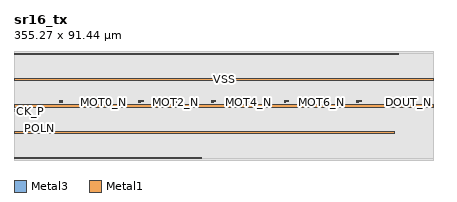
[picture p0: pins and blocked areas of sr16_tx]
MACRO sr16_tx
  CLASS BLOCK ;
  FOREIGN sr16_tx ;
  ORIGIN 0.150 1.000 ;
  SIZE 355.270 BY 91.440 ;
  PIN CK_N
    DIRECTION INPUT ;
    USE SIGNAL ;
    PORT
      LAYER Metal3 ;
        RECT 0.000 41.120 0.150 41.720 ;
    END
  END CK_N
  PIN CK_P
    DIRECTION INPUT ;
    USE SIGNAL ;
    PORT
      LAYER Metal3 ;
        RECT 0.000 40.020 0.150 40.620 ;
    END
  END CK_P
  PIN CLK_W_N
    DIRECTION INPUT ;
    USE SIGNAL ;
    PORT
      LAYER Metal3 ;
        RECT 38.250 47.880 40.470 48.180 ;
    END
  END CLK_W_N
  PIN CLK_W_P
    DIRECTION INPUT ;
    USE SIGNAL ;
    PORT
      LAYER Metal3 ;
        RECT 38.250 48.930 40.470 49.230 ;
    END
  END CLK_W_P
  PIN MOT0_N
    DIRECTION INPUT ;
    USE SIGNAL ;
    PORT
      LAYER Metal3 ;
        RECT 74.650 47.770 76.215 48.070 ;
    END
  END MOT0_N
  PIN MOT0_P
    DIRECTION INPUT ;
    USE SIGNAL ;
    PORT
      LAYER Metal3 ;
        RECT 74.650 48.870 78.460 49.170 ;
    END
  END MOT0_P
  PIN MOT1_N
    DIRECTION INPUT ;
    USE SIGNAL ;
    PORT
      LAYER Metal3 ;
        RECT 105.370 47.770 106.935 48.070 ;
    END
  END MOT1_N
  PIN MOT1_P
    DIRECTION INPUT ;
    USE SIGNAL ;
    PORT
      LAYER Metal3 ;
        RECT 105.370 48.870 109.180 49.170 ;
    END
  END MOT1_P
  PIN MOT2_N
    DIRECTION INPUT ;
    USE SIGNAL ;
    PORT
      LAYER Metal3 ;
        RECT 136.090 47.770 137.655 48.070 ;
    END
  END MOT2_N
  PIN MOT2_P
    DIRECTION INPUT ;
    USE SIGNAL ;
    PORT
      LAYER Metal3 ;
        RECT 136.090 48.870 139.900 49.170 ;
    END
  END MOT2_P
  PIN MOT3_N
    DIRECTION INPUT ;
    USE SIGNAL ;
    PORT
      LAYER Metal3 ;
        RECT 166.810 47.770 168.375 48.070 ;
    END
  END MOT3_N
  PIN MOT3_P
    DIRECTION INPUT ;
    USE SIGNAL ;
    PORT
      LAYER Metal3 ;
        RECT 166.810 48.870 170.620 49.170 ;
    END
  END MOT3_P
  PIN MOT4_N
    DIRECTION INPUT ;
    USE SIGNAL ;
    PORT
      LAYER Metal3 ;
        RECT 197.530 47.770 199.095 48.070 ;
    END
  END MOT4_N
  PIN MOT4_P
    DIRECTION INPUT ;
    USE SIGNAL ;
    PORT
      LAYER Metal3 ;
        RECT 197.530 48.870 201.340 49.170 ;
    END
  END MOT4_P
  PIN MOT5_N
    DIRECTION INPUT ;
    USE SIGNAL ;
    PORT
      LAYER Metal3 ;
        RECT 228.250 47.770 229.815 48.070 ;
    END
  END MOT5_N
  PIN MOT5_P
    DIRECTION INPUT ;
    USE SIGNAL ;
    PORT
      LAYER Metal3 ;
        RECT 228.250 48.870 232.060 49.170 ;
    END
  END MOT5_P
  PIN MOT6_N
    DIRECTION INPUT ;
    USE SIGNAL ;
    PORT
      LAYER Metal3 ;
        RECT 258.970 47.770 260.535 48.070 ;
    END
  END MOT6_N
  PIN MOT6_P
    DIRECTION INPUT ;
    USE SIGNAL ;
    PORT
      LAYER Metal3 ;
        RECT 258.970 48.870 262.780 49.170 ;
    END
  END MOT6_P
  PIN MOT7_N
    DIRECTION INPUT ;
    USE SIGNAL ;
    PORT
      LAYER Metal3 ;
        RECT 289.690 47.770 291.255 48.070 ;
    END
  END MOT7_N
  PIN MOT7_P
    DIRECTION INPUT ;
    USE SIGNAL ;
    PORT
      LAYER Metal3 ;
        RECT 289.690 48.870 293.500 49.170 ;
    END
  END MOT7_P
  PIN DOUT_N
    DIRECTION OUTPUT ;
    USE SIGNAL ;
    PORT
      LAYER Metal3 ;
        RECT 352.900 47.720 353.350 48.320 ;
    END
  END DOUT_N
  PIN DOUT_P
    DIRECTION OUTPUT ;
    USE SIGNAL ;
    PORT
      LAYER Metal3 ;
        RECT 352.390 48.970 353.350 49.270 ;
    END
  END DOUT_P
  PIN POLN
    DIRECTION INPUT ;
    USE SIGNAL ;
    PORT
      LAYER Metal3 ;
        RECT 21.450 25.370 22.120 26.390 ;
    END
  END POLN
  PIN VDD
    DIRECTION INOUT ;
    USE POWER ;
    PORT
      LAYER Metal1 ;
        RECT 0.000 0.000 158.320 1.000 ;
        RECT 0.000 43.720 355.120 45.720 ;
        RECT 0.000 88.440 325.360 89.440 ;
    END
  END VDD
  PIN VSS
    DIRECTION INOUT ;
    USE GROUND ;
    PORT
      LAYER Metal1 ;
        RECT 0.000 21.360 321.520 23.360 ;
        RECT 0.000 66.080 355.120 68.080 ;
    END
  END VSS
  OBS
    LAYER Metal1 ;
      RECT -0.150 -1.000 355.120 0.000 ;
      RECT -0.150 0.000 0.000 1.000 ;
      RECT 158.320 0.000 355.120 1.000 ;
      RECT -0.150 1.000 355.120 21.360 ;
      RECT -0.150 21.360 0.000 23.360 ;
      RECT 321.520 21.360 355.120 23.360 ;
      RECT -0.150 23.360 355.120 43.720 ;
      RECT -0.150 43.720 0.000 45.720 ;
      RECT -0.150 45.720 355.120 66.080 ;
      RECT -0.150 66.080 0.000 68.080 ;
      RECT -0.150 68.080 355.120 88.440 ;
      RECT -0.150 88.440 0.000 89.440 ;
      RECT 325.360 88.440 355.120 89.440 ;
      RECT -0.150 89.440 355.120 90.440 ;
    LAYER Metal2 ;
      RECT -0.150 -1.000 355.120 0.000 ;
      RECT -0.150 0.000 0.000 1.000 ;
      RECT 158.320 0.000 355.120 1.000 ;
      RECT -0.150 1.000 355.120 21.360 ;
      RECT -0.150 21.360 0.000 23.360 ;
      RECT 321.520 21.360 355.120 23.360 ;
      RECT -0.150 23.360 355.120 43.720 ;
      RECT -0.150 43.720 0.000 45.720 ;
      RECT -0.150 45.720 355.120 66.080 ;
      RECT -0.150 66.080 0.000 68.080 ;
      RECT -0.150 68.080 355.120 88.440 ;
      RECT -0.150 88.440 0.000 89.440 ;
      RECT 325.360 88.440 355.120 89.440 ;
      RECT -0.150 89.440 355.120 90.440 ;
    LAYER Metal3 ;
      RECT -0.150 -1.000 355.120 0.000 ;
      RECT -0.150 0.000 0.000 1.000 ;
      RECT 158.320 0.000 355.120 1.000 ;
      RECT -0.150 1.000 355.120 21.360 ;
      RECT -0.150 21.360 0.000 23.360 ;
      RECT 321.520 21.360 355.120 23.360 ;
      RECT -0.150 23.360 355.120 24.890 ;
      RECT -0.150 24.890 20.970 26.870 ;
      RECT 22.600 24.890 355.120 26.870 ;
      RECT -0.150 26.870 355.120 39.540 ;
      RECT 0.630 39.540 355.120 40.640 ;
      RECT 0.630 40.640 355.120 41.100 ;
      RECT 0.630 41.100 355.120 42.200 ;
      RECT -0.150 42.200 355.120 43.720 ;
      RECT -0.150 43.720 0.000 45.720 ;
      RECT -0.150 45.720 355.120 47.240 ;
      RECT -0.150 47.240 352.420 47.290 ;
      RECT 353.830 47.240 355.120 47.290 ;
      RECT -0.150 47.290 74.170 47.400 ;
      RECT 76.695 47.290 104.890 47.400 ;
      RECT 107.415 47.290 135.610 47.400 ;
      RECT 138.135 47.290 166.330 47.400 ;
      RECT 168.855 47.290 197.050 47.400 ;
      RECT 199.575 47.290 227.770 47.400 ;
      RECT 230.295 47.290 258.490 47.400 ;
      RECT 261.015 47.290 289.210 47.400 ;
      RECT 291.735 47.290 352.420 47.400 ;
      RECT 353.830 47.290 355.120 47.400 ;
      RECT -0.150 47.400 37.770 48.390 ;
      RECT 40.950 47.400 74.170 48.390 ;
      RECT 76.695 47.400 104.890 48.390 ;
      RECT 107.415 47.400 135.610 48.390 ;
      RECT 138.135 47.400 166.330 48.390 ;
      RECT 168.855 47.400 197.050 48.390 ;
      RECT 199.575 47.400 227.770 48.390 ;
      RECT 230.295 47.400 258.490 48.390 ;
      RECT 261.015 47.400 289.210 48.390 ;
      RECT 291.735 47.400 352.420 48.390 ;
      RECT 353.830 47.400 355.120 48.390 ;
      RECT -0.150 48.390 37.770 48.450 ;
      RECT 40.950 48.390 74.170 48.450 ;
      RECT 78.940 48.390 104.890 48.450 ;
      RECT 109.660 48.390 135.610 48.450 ;
      RECT 140.380 48.390 166.330 48.450 ;
      RECT 171.100 48.390 197.050 48.450 ;
      RECT 201.820 48.390 227.770 48.450 ;
      RECT 232.540 48.390 258.490 48.450 ;
      RECT 263.260 48.390 289.210 48.450 ;
      RECT 293.980 48.390 352.420 48.450 ;
      RECT 353.830 48.390 355.120 48.450 ;
      RECT -0.150 48.450 37.770 48.490 ;
      RECT 40.950 48.450 74.170 48.490 ;
      RECT 78.940 48.450 104.890 48.490 ;
      RECT 109.660 48.450 135.610 48.490 ;
      RECT 140.380 48.450 166.330 48.490 ;
      RECT 171.100 48.450 197.050 48.490 ;
      RECT 201.820 48.450 227.770 48.490 ;
      RECT 232.540 48.450 258.490 48.490 ;
      RECT 263.260 48.450 289.210 48.490 ;
      RECT 293.980 48.450 352.420 48.490 ;
      RECT 353.830 48.450 355.120 48.490 ;
      RECT -0.150 48.490 37.770 48.550 ;
      RECT 40.950 48.490 74.170 48.550 ;
      RECT 78.940 48.490 104.890 48.550 ;
      RECT 109.660 48.490 135.610 48.550 ;
      RECT 140.380 48.490 166.330 48.550 ;
      RECT 171.100 48.490 197.050 48.550 ;
      RECT 201.820 48.490 227.770 48.550 ;
      RECT 232.540 48.490 258.490 48.550 ;
      RECT 263.260 48.490 289.210 48.550 ;
      RECT 293.980 48.490 351.910 48.550 ;
      RECT 353.830 48.490 355.120 48.550 ;
      RECT -0.150 48.550 37.770 48.660 ;
      RECT 40.950 48.550 74.170 48.660 ;
      RECT 78.940 48.550 104.890 48.660 ;
      RECT 109.660 48.550 135.610 48.660 ;
      RECT 140.380 48.550 166.330 48.660 ;
      RECT 171.100 48.550 197.050 48.660 ;
      RECT 201.820 48.550 227.770 48.660 ;
      RECT 232.540 48.550 258.490 48.660 ;
      RECT 263.260 48.550 289.210 48.660 ;
      RECT 293.980 48.550 351.910 48.660 ;
      RECT 353.830 48.550 355.120 48.660 ;
      RECT -0.150 48.660 37.770 48.800 ;
      RECT 40.950 48.660 74.170 48.800 ;
      RECT 78.940 48.660 104.890 48.800 ;
      RECT 109.660 48.660 135.610 48.800 ;
      RECT 140.380 48.660 166.330 48.800 ;
      RECT 171.100 48.660 197.050 48.800 ;
      RECT 201.820 48.660 227.770 48.800 ;
      RECT 232.540 48.660 258.490 48.800 ;
      RECT 263.260 48.660 289.210 48.800 ;
      RECT 293.980 48.660 351.910 48.800 ;
      RECT 353.830 48.660 355.120 48.800 ;
      RECT -0.150 48.800 37.770 49.650 ;
      RECT 40.950 48.800 74.170 49.650 ;
      RECT 78.940 48.800 104.890 49.650 ;
      RECT 109.660 48.800 135.610 49.650 ;
      RECT 140.380 48.800 166.330 49.650 ;
      RECT 171.100 48.800 197.050 49.650 ;
      RECT 201.820 48.800 227.770 49.650 ;
      RECT 232.540 48.800 258.490 49.650 ;
      RECT 263.260 48.800 289.210 49.650 ;
      RECT 293.980 48.800 351.910 49.650 ;
      RECT 353.830 48.800 355.120 49.650 ;
      RECT -0.150 49.650 37.770 49.710 ;
      RECT 40.950 49.650 351.910 49.710 ;
      RECT 353.830 49.650 355.120 49.710 ;
      RECT -0.150 49.710 351.910 49.750 ;
      RECT 353.830 49.710 355.120 49.750 ;
      RECT -0.150 49.750 355.120 66.080 ;
      RECT -0.150 66.080 0.000 68.080 ;
      RECT -0.150 68.080 355.120 88.440 ;
      RECT -0.150 88.440 0.000 89.440 ;
      RECT 325.360 88.440 355.120 89.440 ;
      RECT -0.150 89.440 355.120 90.440 ;
    LAYER Metal4 ;
      RECT -0.150 -1.000 355.120 0.000 ;
      RECT -0.150 0.000 0.000 1.000 ;
      RECT 158.320 0.000 355.120 1.000 ;
      RECT -0.150 1.000 355.120 21.360 ;
      RECT -0.150 21.360 0.000 23.360 ;
      RECT 321.520 21.360 355.120 23.360 ;
      RECT -0.150 23.360 355.120 24.890 ;
      RECT -0.150 24.890 20.970 26.870 ;
      RECT 22.600 24.890 355.120 26.870 ;
      RECT -0.150 26.870 355.120 39.540 ;
      RECT 0.630 39.540 355.120 40.640 ;
      RECT 0.630 40.640 355.120 41.100 ;
      RECT 0.630 41.100 355.120 42.200 ;
      RECT -0.150 42.200 355.120 43.720 ;
      RECT -0.150 43.720 0.000 45.720 ;
      RECT -0.150 45.720 355.120 47.240 ;
      RECT -0.150 47.240 352.420 47.290 ;
      RECT 353.830 47.240 355.120 47.290 ;
      RECT -0.150 47.290 74.170 47.400 ;
      RECT 76.695 47.290 104.890 47.400 ;
      RECT 107.415 47.290 135.610 47.400 ;
      RECT 138.135 47.290 166.330 47.400 ;
      RECT 168.855 47.290 197.050 47.400 ;
      RECT 199.575 47.290 227.770 47.400 ;
      RECT 230.295 47.290 258.490 47.400 ;
      RECT 261.015 47.290 289.210 47.400 ;
      RECT 291.735 47.290 352.420 47.400 ;
      RECT 353.830 47.290 355.120 47.400 ;
      RECT -0.150 47.400 37.770 48.390 ;
      RECT 40.950 47.400 74.170 48.390 ;
      RECT 76.695 47.400 104.890 48.390 ;
      RECT 107.415 47.400 135.610 48.390 ;
      RECT 138.135 47.400 166.330 48.390 ;
      RECT 168.855 47.400 197.050 48.390 ;
      RECT 199.575 47.400 227.770 48.390 ;
      RECT 230.295 47.400 258.490 48.390 ;
      RECT 261.015 47.400 289.210 48.390 ;
      RECT 291.735 47.400 352.420 48.390 ;
      RECT 353.830 47.400 355.120 48.390 ;
      RECT -0.150 48.390 37.770 48.450 ;
      RECT 40.950 48.390 74.170 48.450 ;
      RECT 78.940 48.390 104.890 48.450 ;
      RECT 109.660 48.390 135.610 48.450 ;
      RECT 140.380 48.390 166.330 48.450 ;
      RECT 171.100 48.390 197.050 48.450 ;
      RECT 201.820 48.390 227.770 48.450 ;
      RECT 232.540 48.390 258.490 48.450 ;
      RECT 263.260 48.390 289.210 48.450 ;
      RECT 293.980 48.390 352.420 48.450 ;
      RECT 353.830 48.390 355.120 48.450 ;
      RECT -0.150 48.450 37.770 48.490 ;
      RECT 40.950 48.450 74.170 48.490 ;
      RECT 78.940 48.450 104.890 48.490 ;
      RECT 109.660 48.450 135.610 48.490 ;
      RECT 140.380 48.450 166.330 48.490 ;
      RECT 171.100 48.450 197.050 48.490 ;
      RECT 201.820 48.450 227.770 48.490 ;
      RECT 232.540 48.450 258.490 48.490 ;
      RECT 263.260 48.450 289.210 48.490 ;
      RECT 293.980 48.450 352.420 48.490 ;
      RECT 353.830 48.450 355.120 48.490 ;
      RECT -0.150 48.490 37.770 48.550 ;
      RECT 40.950 48.490 74.170 48.550 ;
      RECT 78.940 48.490 104.890 48.550 ;
      RECT 109.660 48.490 135.610 48.550 ;
      RECT 140.380 48.490 166.330 48.550 ;
      RECT 171.100 48.490 197.050 48.550 ;
      RECT 201.820 48.490 227.770 48.550 ;
      RECT 232.540 48.490 258.490 48.550 ;
      RECT 263.260 48.490 289.210 48.550 ;
      RECT 293.980 48.490 351.910 48.550 ;
      RECT 353.830 48.490 355.120 48.550 ;
      RECT -0.150 48.550 37.770 48.660 ;
      RECT 40.950 48.550 74.170 48.660 ;
      RECT 78.940 48.550 104.890 48.660 ;
      RECT 109.660 48.550 135.610 48.660 ;
      RECT 140.380 48.550 166.330 48.660 ;
      RECT 171.100 48.550 197.050 48.660 ;
      RECT 201.820 48.550 227.770 48.660 ;
      RECT 232.540 48.550 258.490 48.660 ;
      RECT 263.260 48.550 289.210 48.660 ;
      RECT 293.980 48.550 351.910 48.660 ;
      RECT 353.830 48.550 355.120 48.660 ;
      RECT -0.150 48.660 37.770 48.800 ;
      RECT 40.950 48.660 74.170 48.800 ;
      RECT 78.940 48.660 104.890 48.800 ;
      RECT 109.660 48.660 135.610 48.800 ;
      RECT 140.380 48.660 166.330 48.800 ;
      RECT 171.100 48.660 197.050 48.800 ;
      RECT 201.820 48.660 227.770 48.800 ;
      RECT 232.540 48.660 258.490 48.800 ;
      RECT 263.260 48.660 289.210 48.800 ;
      RECT 293.980 48.660 351.910 48.800 ;
      RECT 353.830 48.660 355.120 48.800 ;
      RECT -0.150 48.800 37.770 49.650 ;
      RECT 40.950 48.800 74.170 49.650 ;
      RECT 78.940 48.800 104.890 49.650 ;
      RECT 109.660 48.800 135.610 49.650 ;
      RECT 140.380 48.800 166.330 49.650 ;
      RECT 171.100 48.800 197.050 49.650 ;
      RECT 201.820 48.800 227.770 49.650 ;
      RECT 232.540 48.800 258.490 49.650 ;
      RECT 263.260 48.800 289.210 49.650 ;
      RECT 293.980 48.800 351.910 49.650 ;
      RECT 353.830 48.800 355.120 49.650 ;
      RECT -0.150 49.650 37.770 49.710 ;
      RECT 40.950 49.650 351.910 49.710 ;
      RECT 353.830 49.650 355.120 49.710 ;
      RECT -0.150 49.710 351.910 49.750 ;
      RECT 353.830 49.710 355.120 49.750 ;
      RECT -0.150 49.750 355.120 66.080 ;
      RECT -0.150 66.080 0.000 68.080 ;
      RECT -0.150 68.080 355.120 88.440 ;
      RECT -0.150 88.440 0.000 89.440 ;
      RECT 325.360 88.440 355.120 89.440 ;
      RECT -0.150 89.440 355.120 90.440 ;
    LAYER Metal4 ;
      RECT 265.235 26.175 265.525 26.465 ;
      RECT 265.280 26.465 265.480 32.355 ;
      RECT 265.235 32.355 265.525 32.645 ;
      RECT 192.275 40.175 192.565 40.465 ;
      RECT 192.320 40.465 192.520 46.395 ;
      RECT 192.275 46.395 192.565 46.685 ;
      RECT 227.755 41.275 228.045 41.565 ;
      RECT 227.800 41.565 228.000 46.915 ;
      RECT 227.755 46.915 228.045 47.205 ;
      RECT 223.915 42.755 224.205 43.045 ;
      RECT 223.960 43.045 224.160 47.875 ;
      RECT 223.915 47.875 224.205 48.165 ;
      RECT 285.355 43.275 285.645 43.565 ;
      RECT 285.400 43.565 285.600 47.875 ;
      RECT 285.355 47.875 285.645 48.165 ;
      RECT 228.755 40.175 229.045 40.465 ;
      RECT 228.800 40.465 229.000 50.035 ;
      RECT 228.755 50.035 229.045 50.325 ;
      RECT 264.235 41.275 264.525 41.565 ;
      RECT 264.280 41.565 264.480 50.555 ;
      RECT 264.235 50.555 264.525 50.845 ;
      RECT 265.235 40.175 265.525 40.465 ;
      RECT 265.280 40.465 265.480 51.075 ;
      RECT 265.235 51.075 265.525 51.365 ;
      RECT 189.355 41.275 189.645 41.565 ;
      RECT 189.400 41.565 189.600 51.595 ;
      RECT 189.355 51.595 189.645 51.885 ;
      RECT 190.355 40.175 190.645 40.465 ;
      RECT 190.400 40.465 190.600 52.115 ;
      RECT 190.355 52.115 190.645 52.405 ;
      RECT 352.555 44.315 352.845 44.605 ;
      RECT 352.600 44.605 352.800 61.875 ;
      RECT 352.555 61.875 352.845 62.165 ;
      RECT 353.555 44.835 353.845 45.125 ;
      RECT 353.600 45.125 353.800 62.975 ;
      RECT 353.555 62.975 353.845 63.265 ;
      RECT 304.555 43.795 304.845 44.085 ;
      RECT 304.600 44.085 304.800 85.995 ;
      RECT 304.555 85.995 304.845 86.285 ;
      RECT 316.575 47.760 316.865 48.280 ;
      RECT 318.495 47.760 318.785 48.280 ;
      RECT 286.355 45.875 286.645 46.165 ;
      RECT 286.400 46.165 286.600 48.975 ;
      RECT 286.355 48.975 286.645 49.265 ;
      RECT 317.995 47.875 318.285 48.165 ;
      RECT 318.040 48.165 318.240 51.595 ;
      RECT 317.995 51.595 318.285 51.885 ;
      RECT 285.855 48.860 286.145 49.380 ;
      RECT 318.995 48.975 319.285 49.265 ;
      RECT 319.040 49.265 319.240 52.115 ;
      RECT 318.995 52.115 319.285 52.405 ;
      RECT 316.575 48.860 316.865 49.380 ;
      RECT 318.495 61.760 318.785 62.280 ;
      RECT 353.055 61.760 353.345 62.280 ;
      RECT 318.495 48.860 318.785 49.380 ;
      RECT 318.495 62.860 318.785 63.380 ;
      RECT 353.055 62.860 353.345 63.380 ;
      RECT 316.075 47.875 316.365 48.165 ;
      RECT 316.120 48.165 316.320 66.675 ;
      RECT 316.075 66.675 316.365 66.965 ;
      RECT 317.075 48.975 317.365 49.265 ;
      RECT 317.120 49.265 317.320 67.195 ;
      RECT 317.075 67.195 317.365 67.485 ;
      RECT 267.155 68.755 267.445 69.045 ;
      RECT 267.200 69.045 267.400 70.895 ;
      RECT 267.155 70.895 267.445 71.185 ;
      RECT 303.635 68.755 303.925 69.045 ;
      RECT 303.680 69.045 303.880 70.895 ;
      RECT 303.635 70.895 303.925 71.185 ;
      RECT 323.795 68.755 324.085 69.045 ;
      RECT 323.840 69.045 324.040 70.895 ;
      RECT 323.795 70.895 324.085 71.185 ;
      RECT 266.655 70.780 266.945 71.300 ;
      RECT 268.575 70.780 268.865 71.300 ;
      RECT 303.135 70.780 303.425 71.300 ;
      RECT 313.215 70.780 313.505 71.300 ;
      RECT 323.295 70.780 323.585 71.300 ;
      RECT 266.655 71.880 266.945 72.400 ;
      RECT 268.575 71.880 268.865 72.400 ;
      RECT 303.135 71.880 303.425 72.400 ;
      RECT 313.215 71.880 313.505 72.400 ;
      RECT 323.295 71.880 323.585 72.400 ;
      RECT 266.155 71.995 266.445 72.285 ;
      RECT 266.200 72.285 266.400 72.915 ;
      RECT 266.155 72.915 266.445 73.205 ;
      RECT 302.635 71.995 302.925 72.285 ;
      RECT 302.680 72.285 302.880 72.915 ;
      RECT 302.635 72.915 302.925 73.205 ;
      RECT 322.795 71.995 323.085 72.285 ;
      RECT 322.840 72.285 323.040 72.915 ;
      RECT 322.795 72.915 323.085 73.205 ;
      RECT 317.995 61.875 318.285 62.165 ;
      RECT 318.040 62.165 318.240 73.955 ;
      RECT 317.995 73.955 318.285 74.245 ;
      RECT 269.575 70.895 269.865 71.185 ;
      RECT 269.620 71.185 269.820 77.075 ;
      RECT 269.575 77.075 269.865 77.365 ;
      RECT 313.715 70.895 314.005 71.185 ;
      RECT 313.760 71.185 313.960 78.115 ;
      RECT 313.715 78.115 314.005 78.405 ;
      RECT 312.715 71.995 313.005 72.285 ;
      RECT 312.760 72.285 312.960 79.155 ;
      RECT 312.715 79.155 313.005 79.445 ;
      RECT 267.575 71.995 267.865 72.285 ;
      RECT 267.620 72.285 267.820 79.675 ;
      RECT 267.575 79.675 267.865 79.965 ;
      RECT 318.995 62.975 319.285 63.265 ;
      RECT 319.040 63.265 319.240 80.195 ;
      RECT 318.995 80.195 319.285 80.485 ;
      RECT 267.155 83.315 267.445 83.605 ;
      RECT 267.200 83.605 267.400 84.895 ;
      RECT 267.155 84.895 267.445 85.185 ;
      RECT 269.075 60.955 269.365 61.245 ;
      RECT 269.120 61.245 269.320 84.895 ;
      RECT 269.075 84.895 269.365 85.185 ;
      RECT 303.635 82.795 303.925 83.085 ;
      RECT 303.680 83.085 303.880 84.895 ;
      RECT 303.635 84.895 303.925 85.185 ;
      RECT 305.555 45.355 305.845 45.645 ;
      RECT 305.600 45.645 305.800 84.895 ;
      RECT 305.555 84.895 305.845 85.185 ;
      RECT 315.635 78.115 315.925 78.405 ;
      RECT 315.680 78.405 315.880 84.895 ;
      RECT 315.635 84.895 315.925 85.185 ;
      RECT 266.655 84.780 266.945 85.300 ;
      RECT 268.575 84.780 268.865 85.300 ;
      RECT 303.135 84.780 303.425 85.300 ;
      RECT 305.055 84.780 305.345 85.300 ;
      RECT 315.135 84.780 315.425 85.300 ;
      RECT 268.075 65.115 268.365 65.405 ;
      RECT 268.120 65.405 268.320 85.995 ;
      RECT 268.075 85.995 268.365 86.285 ;
      RECT 285.855 47.760 286.145 48.280 ;
      RECT 314.635 79.155 314.925 79.445 ;
      RECT 314.680 79.445 314.880 85.995 ;
      RECT 314.635 85.995 314.925 86.285 ;
      RECT 266.655 85.880 266.945 86.400 ;
      RECT 268.575 85.880 268.865 86.400 ;
      RECT 303.135 85.880 303.425 86.400 ;
      RECT 305.055 85.880 305.345 86.400 ;
      RECT 315.135 85.880 315.425 86.400 ;
      RECT 266.155 85.995 266.445 86.285 ;
      RECT 266.200 86.285 266.400 87.475 ;
      RECT 266.155 87.475 266.445 87.765 ;
      RECT 302.635 85.995 302.925 86.285 ;
      RECT 302.680 86.285 302.880 87.995 ;
      RECT 302.635 87.995 302.925 88.285 ;
      RECT 193.195 47.875 193.485 48.165 ;
      RECT 193.240 48.165 193.440 65.635 ;
      RECT 193.195 65.635 193.485 65.925 ;
      RECT 254.635 47.875 254.925 48.165 ;
      RECT 254.680 48.165 254.880 66.155 ;
      RECT 254.635 66.155 254.925 66.445 ;
      RECT 224.915 46.395 225.205 46.685 ;
      RECT 224.960 46.685 225.160 48.975 ;
      RECT 224.915 48.975 225.205 49.265 ;
      RECT 194.195 80.195 194.485 80.485 ;
      RECT 194.240 80.485 194.440 84.895 ;
      RECT 194.195 84.895 194.485 85.185 ;
      RECT 196.115 67.715 196.405 68.005 ;
      RECT 196.160 68.005 196.360 84.895 ;
      RECT 196.115 84.895 196.405 85.185 ;
      RECT 230.675 83.835 230.965 84.125 ;
      RECT 230.720 84.125 230.920 84.895 ;
      RECT 230.675 84.895 230.965 85.185 ;
      RECT 232.595 68.235 232.885 68.525 ;
      RECT 232.640 68.525 232.840 84.895 ;
      RECT 232.595 84.895 232.885 85.185 ;
      RECT 195.615 71.880 195.905 72.400 ;
      RECT 230.175 71.880 230.465 72.400 ;
      RECT 232.095 71.880 232.385 72.400 ;
      RECT 193.695 47.760 193.985 48.280 ;
      RECT 255.635 48.975 255.925 49.265 ;
      RECT 255.680 49.265 255.880 67.715 ;
      RECT 255.635 67.715 255.925 68.005 ;
      RECT 193.695 84.780 193.985 85.300 ;
      RECT 195.615 84.780 195.905 85.300 ;
      RECT 230.175 84.780 230.465 85.300 ;
      RECT 232.095 84.780 232.385 85.300 ;
      RECT 194.195 48.975 194.485 49.265 ;
      RECT 194.240 49.265 194.440 68.235 ;
      RECT 194.195 68.235 194.485 68.525 ;
      RECT 193.695 48.860 193.985 49.380 ;
      RECT 224.415 48.860 224.705 49.380 ;
      RECT 255.135 48.860 255.425 49.380 ;
      RECT 195.615 70.780 195.905 71.300 ;
      RECT 193.195 73.955 193.485 74.245 ;
      RECT 193.240 74.245 193.440 85.995 ;
      RECT 193.195 85.995 193.485 86.285 ;
      RECT 195.115 66.155 195.405 66.445 ;
      RECT 195.160 66.445 195.360 85.995 ;
      RECT 195.115 85.995 195.405 86.285 ;
      RECT 231.595 65.635 231.885 65.925 ;
      RECT 231.640 65.925 231.840 85.995 ;
      RECT 231.595 85.995 231.885 86.285 ;
      RECT 230.175 70.780 230.465 71.300 ;
      RECT 232.095 70.780 232.385 71.300 ;
      RECT 224.415 47.760 224.705 48.280 ;
      RECT 193.695 85.880 193.985 86.400 ;
      RECT 195.615 85.880 195.905 86.400 ;
      RECT 230.175 85.880 230.465 86.400 ;
      RECT 232.095 85.880 232.385 86.400 ;
      RECT 233.595 70.895 233.885 71.185 ;
      RECT 233.640 71.185 233.840 77.595 ;
      RECT 233.595 77.595 233.885 77.885 ;
      RECT 196.615 70.895 196.905 71.185 ;
      RECT 196.660 71.185 196.860 78.115 ;
      RECT 196.615 78.115 196.905 78.405 ;
      RECT 230.675 70.895 230.965 71.185 ;
      RECT 230.720 71.185 230.920 78.115 ;
      RECT 230.675 78.115 230.965 78.405 ;
      RECT 255.135 47.760 255.425 48.280 ;
      RECT 233.095 71.995 233.385 72.285 ;
      RECT 233.140 72.285 233.340 78.635 ;
      RECT 233.095 78.635 233.385 78.925 ;
      RECT 229.675 85.995 229.965 86.285 ;
      RECT 229.720 86.285 229.920 86.955 ;
      RECT 229.675 86.955 229.965 87.245 ;
      RECT 194.615 71.995 194.905 72.285 ;
      RECT 194.660 72.285 194.860 79.155 ;
      RECT 194.615 79.155 194.905 79.445 ;
      RECT 229.675 71.995 229.965 72.285 ;
      RECT 229.720 72.285 229.920 79.155 ;
      RECT 229.675 79.155 229.965 79.445 ;
      RECT 191.275 41.275 191.565 41.565 ;
      RECT 191.320 41.565 191.520 42.755 ;
      RECT 191.275 42.755 191.565 43.045 ;
      RECT 191.775 26.060 192.065 26.580 ;
      RECT 226.335 26.060 226.625 26.580 ;
      RECT 228.255 26.060 228.545 26.580 ;
      RECT 262.815 26.060 263.105 26.580 ;
      RECT 264.735 26.060 265.025 26.580 ;
      RECT 191.775 27.160 192.065 27.680 ;
      RECT 226.335 27.160 226.625 27.680 ;
      RECT 228.255 27.160 228.545 27.680 ;
      RECT 262.815 27.160 263.105 27.680 ;
      RECT 264.735 27.160 265.025 27.680 ;
      RECT 262.315 27.275 262.605 27.565 ;
      RECT 262.360 27.565 262.560 28.195 ;
      RECT 262.315 28.195 262.605 28.485 ;
      RECT 263.315 24.035 263.605 24.325 ;
      RECT 263.360 24.325 263.560 26.175 ;
      RECT 263.315 26.175 263.605 26.465 ;
      RECT 228.755 26.175 229.045 26.465 ;
      RECT 228.800 26.465 229.000 32.875 ;
      RECT 228.755 32.875 229.045 33.165 ;
      RECT 192.275 26.175 192.565 26.465 ;
      RECT 192.320 26.465 192.520 33.395 ;
      RECT 192.275 33.395 192.565 33.685 ;
      RECT 226.835 26.175 227.125 26.465 ;
      RECT 226.880 26.465 227.080 33.395 ;
      RECT 226.835 33.395 227.125 33.685 ;
      RECT 227.755 27.275 228.045 27.565 ;
      RECT 227.800 27.565 228.000 33.915 ;
      RECT 227.755 33.915 228.045 34.205 ;
      RECT 191.275 27.275 191.565 27.565 ;
      RECT 191.320 27.565 191.520 34.435 ;
      RECT 191.275 34.435 191.565 34.725 ;
      RECT 225.835 27.275 226.125 27.565 ;
      RECT 225.880 27.565 226.080 34.435 ;
      RECT 225.835 34.435 226.125 34.725 ;
      RECT 264.235 27.275 264.525 27.565 ;
      RECT 264.280 27.565 264.480 34.955 ;
      RECT 264.235 34.955 264.525 35.245 ;
      RECT 226.835 39.115 227.125 39.405 ;
      RECT 226.880 39.405 227.080 40.175 ;
      RECT 226.835 40.175 227.125 40.465 ;
      RECT 263.315 38.075 263.605 38.365 ;
      RECT 263.360 38.365 263.560 40.175 ;
      RECT 263.315 40.175 263.605 40.465 ;
      RECT 189.855 40.060 190.145 40.580 ;
      RECT 191.775 40.060 192.065 40.580 ;
      RECT 226.335 40.060 226.625 40.580 ;
      RECT 228.255 40.060 228.545 40.580 ;
      RECT 262.815 40.060 263.105 40.580 ;
      RECT 264.735 40.060 265.025 40.580 ;
      RECT 262.315 38.595 262.605 38.885 ;
      RECT 262.360 38.885 262.560 41.275 ;
      RECT 262.315 41.275 262.605 41.565 ;
      RECT 189.855 41.160 190.145 41.680 ;
      RECT 191.775 41.160 192.065 41.680 ;
      RECT 226.335 41.160 226.625 41.680 ;
      RECT 228.255 41.160 228.545 41.680 ;
      RECT 262.815 41.160 263.105 41.680 ;
      RECT 264.735 41.160 265.025 41.680 ;
      RECT 225.835 41.275 226.125 41.565 ;
      RECT 225.880 41.565 226.080 42.235 ;
      RECT 225.835 42.235 226.125 42.525 ;
      RECT 300.715 21.955 301.005 22.245 ;
      RECT 300.760 22.245 300.960 41.275 ;
      RECT 300.715 41.275 301.005 41.565 ;
      RECT 310.795 34.435 311.085 34.725 ;
      RECT 310.840 34.725 311.040 41.275 ;
      RECT 310.795 41.275 311.085 41.565 ;
      RECT 319.455 27.160 319.745 27.680 ;
      RECT 308.875 27.275 309.165 27.565 ;
      RECT 308.920 27.565 309.120 34.435 ;
      RECT 308.875 34.435 309.165 34.725 ;
      RECT 319.955 24.035 320.245 24.325 ;
      RECT 320.000 24.325 320.200 26.175 ;
      RECT 319.955 26.175 320.245 26.465 ;
      RECT 298.795 27.275 299.085 27.565 ;
      RECT 298.840 27.565 299.040 28.195 ;
      RECT 298.795 28.195 299.085 28.485 ;
      RECT 318.955 27.275 319.245 27.565 ;
      RECT 319.000 27.565 319.200 28.195 ;
      RECT 318.955 28.195 319.245 28.485 ;
      RECT 299.795 37.035 300.085 37.325 ;
      RECT 299.840 37.325 300.040 40.175 ;
      RECT 299.795 40.175 300.085 40.465 ;
      RECT 299.295 41.160 299.585 41.680 ;
      RECT 301.215 41.160 301.505 41.680 ;
      RECT 311.295 41.160 311.585 41.680 ;
      RECT 301.715 22.475 302.005 22.765 ;
      RECT 301.760 22.765 301.960 40.175 ;
      RECT 301.715 40.175 302.005 40.465 ;
      RECT 311.795 33.395 312.085 33.685 ;
      RECT 311.840 33.685 312.040 40.175 ;
      RECT 311.795 40.175 312.085 40.465 ;
      RECT 299.795 24.035 300.085 24.325 ;
      RECT 299.840 24.325 300.040 26.175 ;
      RECT 299.795 26.175 300.085 26.465 ;
      RECT 299.295 26.060 299.585 26.580 ;
      RECT 309.375 26.060 309.665 26.580 ;
      RECT 319.455 26.060 319.745 26.580 ;
      RECT 309.875 26.175 310.165 26.465 ;
      RECT 309.920 26.465 310.120 33.395 ;
      RECT 309.875 33.395 310.165 33.685 ;
      RECT 299.295 27.160 299.585 27.680 ;
      RECT 299.295 40.060 299.585 40.580 ;
      RECT 301.215 40.060 301.505 40.580 ;
      RECT 311.295 40.060 311.585 40.580 ;
      RECT 309.375 27.160 309.665 27.680 ;
      RECT 298.795 37.555 299.085 37.845 ;
      RECT 298.840 37.845 299.040 41.275 ;
      RECT 298.795 41.275 299.085 41.565 ;
      RECT 72.735 42.235 73.025 42.525 ;
      RECT 72.780 42.525 72.980 64.075 ;
      RECT 72.735 64.075 73.025 64.365 ;
      RECT 72.780 64.365 72.980 66.675 ;
      RECT 72.735 66.675 73.025 66.965 ;
      RECT 35.335 25.075 35.625 25.365 ;
      RECT 35.380 25.365 35.580 69.795 ;
      RECT 35.335 69.795 35.625 70.085 ;
      RECT 142.355 4.255 142.645 4.545 ;
      RECT 142.400 4.545 142.600 45.355 ;
      RECT 142.355 45.355 142.645 45.645 ;
      RECT 0.655 21.955 0.945 22.245 ;
      RECT 0.700 22.245 0.900 41.275 ;
      RECT 0.655 41.275 0.945 41.565 ;
      RECT 0.700 41.565 0.900 84.895 ;
      RECT 0.655 84.895 0.945 85.185 ;
      RECT 71.315 40.175 71.605 40.465 ;
      RECT 71.360 40.465 71.560 45.875 ;
      RECT 71.315 45.875 71.605 46.165 ;
      RECT 37.755 24.035 38.045 24.325 ;
      RECT 37.800 24.325 38.000 47.875 ;
      RECT 37.755 47.875 38.045 48.165 ;
      RECT 38.755 28.195 39.045 28.485 ;
      RECT 38.800 28.485 39.000 48.975 ;
      RECT 38.755 48.975 39.045 49.265 ;
      RECT 1.155 22.475 1.445 22.765 ;
      RECT 1.200 22.765 1.400 40.175 ;
      RECT 1.155 40.175 1.445 40.465 ;
      RECT 1.200 40.465 1.400 85.995 ;
      RECT 1.155 85.995 1.445 86.285 ;
      RECT 133.755 77.595 134.045 77.885 ;
      RECT 133.800 77.885 134.000 84.895 ;
      RECT 133.755 84.895 134.045 85.185 ;
      RECT 136.595 83.315 136.885 83.605 ;
      RECT 136.640 83.605 136.840 84.895 ;
      RECT 136.595 84.895 136.885 85.185 ;
      RECT 163.975 77.075 164.265 77.365 ;
      RECT 164.020 77.365 164.220 84.895 ;
      RECT 163.975 84.895 164.265 85.185 ;
      RECT 167.315 82.795 167.605 83.085 ;
      RECT 167.360 83.085 167.560 84.895 ;
      RECT 167.315 84.895 167.605 85.185 ;
      RECT 132.755 48.975 133.045 49.265 ;
      RECT 132.800 49.265 133.000 60.955 ;
      RECT 132.755 60.955 133.045 61.245 ;
      RECT 131.755 47.875 132.045 48.165 ;
      RECT 131.800 48.165 132.000 65.115 ;
      RECT 131.755 65.115 132.045 65.405 ;
      RECT 162.475 46.915 162.765 47.205 ;
      RECT 162.520 47.205 162.720 47.875 ;
      RECT 162.475 47.875 162.765 48.165 ;
      RECT 101.535 47.760 101.825 48.280 ;
      RECT 101.535 84.780 101.825 85.300 ;
      RECT 105.375 84.780 105.665 85.300 ;
      RECT 132.255 84.780 132.545 85.300 ;
      RECT 136.095 84.780 136.385 85.300 ;
      RECT 162.975 84.780 163.265 85.300 ;
      RECT 166.815 84.780 167.105 85.300 ;
      RECT 132.255 47.760 132.545 48.280 ;
      RECT 162.975 47.760 163.265 48.280 ;
      RECT 102.535 78.115 102.825 78.405 ;
      RECT 102.580 78.405 102.780 84.895 ;
      RECT 102.535 84.895 102.825 85.185 ;
      RECT 105.875 83.835 106.165 84.125 ;
      RECT 105.920 84.125 106.120 84.895 ;
      RECT 105.875 84.895 106.165 85.185 ;
      RECT 100.535 79.155 100.825 79.445 ;
      RECT 100.580 79.445 100.780 85.995 ;
      RECT 100.535 85.995 100.825 86.285 ;
      RECT 133.255 78.635 133.545 78.925 ;
      RECT 133.300 78.925 133.500 85.995 ;
      RECT 133.255 85.995 133.545 86.285 ;
      RECT 161.975 79.675 162.265 79.965 ;
      RECT 162.020 79.965 162.220 85.995 ;
      RECT 161.975 85.995 162.265 86.285 ;
      RECT 101.535 48.860 101.825 49.380 ;
      RECT 132.255 48.860 132.545 49.380 ;
      RECT 162.975 48.860 163.265 49.380 ;
      RECT 101.535 85.880 101.825 86.400 ;
      RECT 105.375 85.880 105.665 86.400 ;
      RECT 132.255 85.880 132.545 86.400 ;
      RECT 136.095 85.880 136.385 86.400 ;
      RECT 162.975 85.880 163.265 86.400 ;
      RECT 166.815 85.880 167.105 86.400 ;
      RECT 163.475 48.975 163.765 49.265 ;
      RECT 163.520 49.265 163.720 50.035 ;
      RECT 163.475 50.035 163.765 50.325 ;
      RECT 101.035 47.875 101.325 48.165 ;
      RECT 101.080 48.165 101.280 50.555 ;
      RECT 101.035 50.555 101.325 50.845 ;
      RECT 104.875 85.995 105.165 86.285 ;
      RECT 104.920 86.285 105.120 86.955 ;
      RECT 104.875 86.955 105.165 87.245 ;
      RECT 135.595 85.995 135.885 86.285 ;
      RECT 135.640 86.285 135.840 87.475 ;
      RECT 135.595 87.475 135.885 87.765 ;
      RECT 102.035 48.975 102.325 49.265 ;
      RECT 102.080 49.265 102.280 51.075 ;
      RECT 102.035 51.075 102.325 51.365 ;
      RECT 166.315 85.995 166.605 86.285 ;
      RECT 166.360 86.285 166.560 87.995 ;
      RECT 166.315 87.995 166.605 88.285 ;
      RECT 38.255 48.860 38.545 49.380 ;
      RECT 0.155 84.780 0.445 85.300 ;
      RECT 74.655 84.780 74.945 85.300 ;
      RECT 74.155 66.675 74.445 66.965 ;
      RECT 74.200 66.965 74.400 85.995 ;
      RECT 74.155 85.995 74.445 86.285 ;
      RECT 0.155 85.880 0.445 86.400 ;
      RECT 74.655 85.880 74.945 86.400 ;
      RECT 34.335 66.675 34.625 66.965 ;
      RECT 34.380 66.965 34.580 69.680 ;
      RECT 34.335 69.680 34.625 70.200 ;
      RECT 38.255 47.760 38.545 48.280 ;
      RECT 75.155 67.195 75.445 67.485 ;
      RECT 75.200 67.485 75.400 84.895 ;
      RECT 75.155 84.895 75.445 85.185 ;
      RECT 70.315 41.275 70.605 41.565 ;
      RECT 70.360 41.565 70.560 43.275 ;
      RECT 70.315 43.275 70.605 43.565 ;
      RECT 33.835 27.275 34.125 27.565 ;
      RECT 33.880 27.565 34.080 44.315 ;
      RECT 33.835 44.315 34.125 44.605 ;
      RECT 34.835 26.175 35.125 26.465 ;
      RECT 34.880 26.465 35.080 44.835 ;
      RECT 34.835 44.835 35.125 45.125 ;
      RECT 35.415 4.255 35.705 4.545 ;
      RECT 35.460 4.545 35.660 22.475 ;
      RECT 35.415 22.475 35.705 22.765 ;
      RECT 34.915 3.155 35.205 3.445 ;
      RECT 34.960 3.445 35.160 21.955 ;
      RECT 34.915 21.955 35.205 22.245 ;
      RECT 34.415 4.140 34.705 4.660 ;
      RECT 34.335 26.060 34.625 26.580 ;
      RECT 70.815 3.040 71.105 3.560 ;
      RECT 70.315 3.155 70.605 3.445 ;
      RECT 70.360 3.445 70.560 24.035 ;
      RECT 70.315 24.035 70.605 24.325 ;
      RECT 34.335 24.960 34.625 25.480 ;
      RECT 34.335 27.160 34.625 27.680 ;
      RECT 34.415 3.040 34.705 3.560 ;
      RECT 70.815 4.140 71.105 4.660 ;
      RECT 0.155 41.160 0.445 41.680 ;
      RECT 0.155 40.060 0.445 40.580 ;
      RECT 70.815 41.160 71.105 41.680 ;
      RECT 71.315 4.255 71.605 4.545 ;
      RECT 71.360 4.545 71.560 28.195 ;
      RECT 71.315 28.195 71.605 28.485 ;
      RECT 68.895 19.355 69.185 19.645 ;
      RECT 68.940 19.645 69.140 42.235 ;
      RECT 68.895 42.235 69.185 42.525 ;
      RECT 70.815 40.060 71.105 40.580 ;
      RECT 101.535 41.160 101.825 41.680 ;
      RECT 128.415 41.160 128.705 41.680 ;
      RECT 132.255 41.160 132.545 41.680 ;
      RECT 159.135 41.160 159.425 41.680 ;
      RECT 162.975 41.160 163.265 41.680 ;
      RECT 128.415 4.140 128.705 4.660 ;
      RECT 141.855 4.140 142.145 4.660 ;
      RECT 143.775 4.140 144.065 4.660 ;
      RECT 156.255 4.140 156.545 4.660 ;
      RECT 98.195 4.255 98.485 4.545 ;
      RECT 98.240 4.545 98.440 5.315 ;
      RECT 98.195 5.315 98.485 5.605 ;
      RECT 155.755 3.155 156.045 3.445 ;
      RECT 155.800 3.445 156.000 21.955 ;
      RECT 155.755 21.955 156.045 22.245 ;
      RECT 128.415 3.040 128.705 3.560 ;
      RECT 128.915 4.255 129.205 4.545 ;
      RECT 128.960 4.545 129.160 22.475 ;
      RECT 128.915 22.475 129.205 22.765 ;
      RECT 156.755 4.255 157.045 4.545 ;
      RECT 156.800 4.545 157.000 22.475 ;
      RECT 156.755 22.475 157.045 22.765 ;
      RECT 98.195 33.395 98.485 33.685 ;
      RECT 98.240 33.685 98.440 40.175 ;
      RECT 98.195 40.175 98.485 40.465 ;
      RECT 102.035 39.115 102.325 39.405 ;
      RECT 102.080 39.405 102.280 40.175 ;
      RECT 102.035 40.175 102.325 40.465 ;
      RECT 144.275 4.255 144.565 4.545 ;
      RECT 144.320 4.545 144.520 5.315 ;
      RECT 144.275 5.315 144.565 5.605 ;
      RECT 124.075 3.155 124.365 3.445 ;
      RECT 124.120 3.445 124.320 10.515 ;
      RECT 124.075 10.515 124.365 10.805 ;
      RECT 125.075 4.255 125.365 4.545 ;
      RECT 125.120 4.545 125.320 11.035 ;
      RECT 125.075 11.035 125.365 11.325 ;
      RECT 141.855 3.040 142.145 3.560 ;
      RECT 101.035 41.275 101.325 41.565 ;
      RECT 101.080 41.565 101.280 42.235 ;
      RECT 101.035 42.235 101.325 42.525 ;
      RECT 144.275 11.035 144.565 11.325 ;
      RECT 144.320 11.325 144.520 17.155 ;
      RECT 144.275 17.155 144.565 17.445 ;
      RECT 128.915 32.875 129.205 33.165 ;
      RECT 128.960 33.165 129.160 40.175 ;
      RECT 128.915 40.175 129.205 40.465 ;
      RECT 132.755 38.075 133.045 38.365 ;
      RECT 132.800 38.365 133.000 40.175 ;
      RECT 132.755 40.175 133.045 40.465 ;
      RECT 143.775 17.040 144.065 17.560 ;
      RECT 97.695 40.060 97.985 40.580 ;
      RECT 141.355 3.155 141.645 3.445 ;
      RECT 141.400 3.445 141.600 43.795 ;
      RECT 141.355 43.795 141.645 44.085 ;
      RECT 143.775 3.040 144.065 3.560 ;
      RECT 156.255 3.040 156.545 3.560 ;
      RECT 159.135 40.060 159.425 40.580 ;
      RECT 97.195 34.435 97.485 34.725 ;
      RECT 97.240 34.725 97.440 41.275 ;
      RECT 97.195 41.275 97.485 41.565 ;
      RECT 162.975 40.060 163.265 40.580 ;
      RECT 101.535 40.060 101.825 40.580 ;
      RECT 127.915 33.915 128.205 34.205 ;
      RECT 127.960 34.205 128.160 41.275 ;
      RECT 127.915 41.275 128.205 41.565 ;
      RECT 131.755 38.595 132.045 38.885 ;
      RECT 131.800 38.885 132.000 41.275 ;
      RECT 131.755 41.275 132.045 41.565 ;
      RECT 158.635 34.955 158.925 35.245 ;
      RECT 158.680 35.245 158.880 41.275 ;
      RECT 158.635 41.275 158.925 41.565 ;
      RECT 159.635 32.355 159.925 32.645 ;
      RECT 159.680 32.645 159.880 40.175 ;
      RECT 159.635 40.175 159.925 40.465 ;
      RECT 163.475 37.035 163.765 37.325 ;
      RECT 163.520 37.325 163.720 40.175 ;
      RECT 163.475 40.175 163.765 40.465 ;
      RECT 162.475 37.555 162.765 37.845 ;
      RECT 162.520 37.845 162.720 41.275 ;
      RECT 162.475 41.275 162.765 41.565 ;
      RECT 128.415 40.060 128.705 40.580 ;
      RECT 97.195 2.195 97.485 2.485 ;
      RECT 97.240 2.485 97.440 3.155 ;
      RECT 97.195 3.155 97.485 3.445 ;
      RECT 143.275 2.195 143.565 2.485 ;
      RECT 143.320 2.485 143.520 3.155 ;
      RECT 143.275 3.155 143.565 3.445 ;
      RECT 97.695 3.040 97.985 3.560 ;
      RECT 143.275 10.515 143.565 10.805 ;
      RECT 143.320 10.805 143.520 18.255 ;
      RECT 143.275 18.255 143.565 18.545 ;
      RECT 143.775 18.140 144.065 18.660 ;
      RECT 97.695 4.140 97.985 4.660 ;
      RECT 124.575 4.140 124.865 4.660 ;
      RECT 124.575 3.040 124.865 3.560 ;
      RECT 127.915 3.155 128.205 3.445 ;
      RECT 127.960 3.445 128.160 21.955 ;
      RECT 127.915 21.955 128.205 22.245 ;
      RECT 132.255 40.060 132.545 40.580 ;
      RECT 97.695 41.160 97.985 41.680 ;
    LAYER Metal5 ;
      RECT 0.000 0.000 355.120 89.440 ;
  END
END sr16_tx
